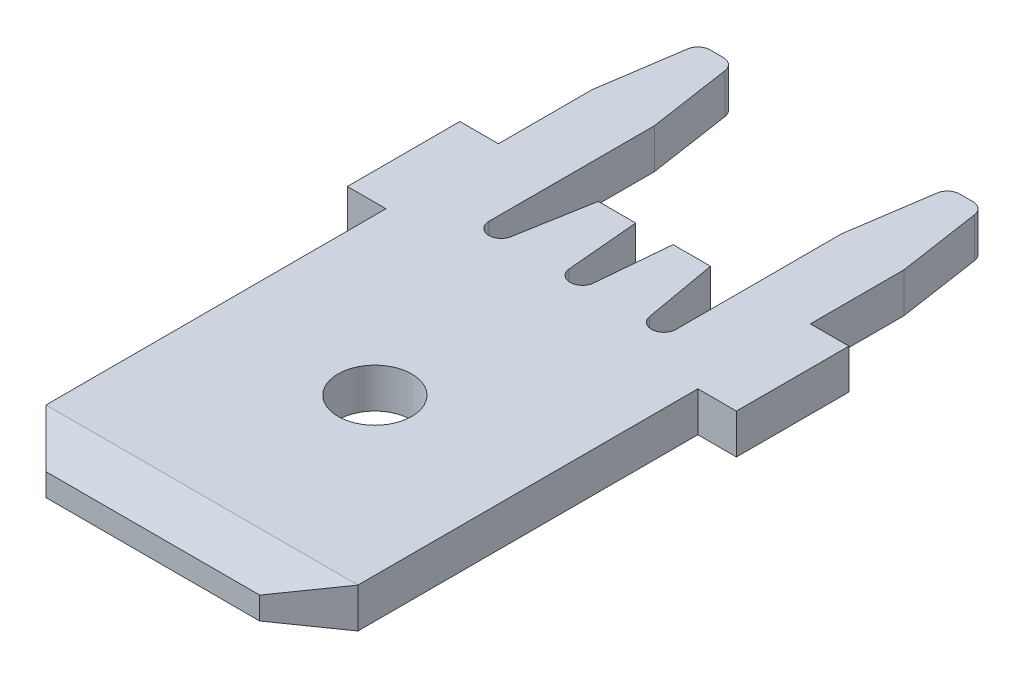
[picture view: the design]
ISO-10303-21;
HEADER;
FILE_DESCRIPTION(('STEP AP214'),'2;1');
FILE_NAME('part.step','',(''),(''),'','','');
FILE_SCHEMA(('AUTOMOTIVE_DESIGN { 1 0 10303 214 1 1 1 1 }'));
ENDSEC;
DATA;
#1=APPLICATION_CONTEXT('core data for automotive mechanical design processes');
#2=APPLICATION_PROTOCOL_DEFINITION('international standard','automotive_design',2000,#1);
#3=PRODUCT_CONTEXT('',#1,'mechanical');
#4=PRODUCT('Part','Part','',(#3));
#5=PRODUCT_RELATED_PRODUCT_CATEGORY('part','',(#4));
#6=PRODUCT_DEFINITION_FORMATION('','',#4);
#7=PRODUCT_DEFINITION_CONTEXT('part definition',#1,'design');
#8=PRODUCT_DEFINITION('design','',#6,#7);
#9=PRODUCT_DEFINITION_SHAPE('','',#8);
#10=(LENGTH_UNIT() NAMED_UNIT(*) SI_UNIT(.MILLI.,.METRE.));
#11=(NAMED_UNIT(*) PLANE_ANGLE_UNIT() SI_UNIT($,.RADIAN.));
#12=(NAMED_UNIT(*) SI_UNIT($,.STERADIAN.) SOLID_ANGLE_UNIT());
#13=UNCERTAINTY_MEASURE_WITH_UNIT(LENGTH_MEASURE(1.E-05),#10,'distance_accuracy_value','');
#14=(GEOMETRIC_REPRESENTATION_CONTEXT(3) GLOBAL_UNCERTAINTY_ASSIGNED_CONTEXT((#13)) GLOBAL_UNIT_ASSIGNED_CONTEXT((#10,
#11,#12)) REPRESENTATION_CONTEXT('',''));
#15=CARTESIAN_POINT('',(0.,0.,0.));
#16=DIRECTION('',(0.,0.,1.));
#17=DIRECTION('',(1.,0.,0.));
#18=AXIS2_PLACEMENT_3D('',#15,#16,#17);
#19=CARTESIAN_POINT('',(-2.67461930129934,-0.81,-9.24999999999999));
#20=DIRECTION('',(0.,-1.,0.));
#21=DIRECTION('',(0.,0.,-1.));
#22=AXIS2_PLACEMENT_3D('',#19,#20,#21);
#23=PLANE('',#22);
#24=DIRECTION('',(0.,0.,1.));
#25=VECTOR('',#24,1.);
#26=CARTESIAN_POINT('',(3.175,-0.81,4.52));
#27=LINE('',#26,#25);
#28=CARTESIAN_POINT('',(3.175,-0.81,-3.4));
#29=VERTEX_POINT('',#28);
#30=CARTESIAN_POINT('',(3.175,-0.81,3.51999999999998));
#31=VERTEX_POINT('',#30);
#32=EDGE_CURVE('E769',#29,#31,#27,.T.);
#33=ORIENTED_EDGE('',*,*,#32,.T.);
#34=DIRECTION('',(-1.,0.,0.));
#35=VECTOR('',#34,1.);
#36=CARTESIAN_POINT('',(-3.175,-0.81,3.51999999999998));
#37=LINE('',#36,#35);
#38=CARTESIAN_POINT('',(-3.175,-0.81,3.51999999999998));
#39=VERTEX_POINT('',#38);
#40=EDGE_CURVE('E262',#31,#39,#37,.T.);
#41=ORIENTED_EDGE('',*,*,#40,.T.);
#42=DIRECTION('',(0.,0.,-1.));
#43=VECTOR('',#42,1.);
#44=CARTESIAN_POINT('',(-3.175,-0.81,4.52));
#45=LINE('',#44,#43);
#46=CARTESIAN_POINT('',(-3.175,-0.81,-3.4));
#47=VERTEX_POINT('',#46);
#48=EDGE_CURVE('E256',#39,#47,#45,.T.);
#49=ORIENTED_EDGE('',*,*,#48,.T.);
#50=DIRECTION('',(-1.,0.,0.));
#51=VECTOR('',#50,1.);
#52=CARTESIAN_POINT('',(-3.175,-0.81,-3.4));
#53=LINE('',#52,#51);
#54=CARTESIAN_POINT('',(-3.96,-0.81,-3.4));
#55=VERTEX_POINT('',#54);
#56=EDGE_CURVE('E260',#47,#55,#53,.T.);
#57=ORIENTED_EDGE('',*,*,#56,.T.);
#58=DIRECTION('',(0.,0.,-1.));
#59=VECTOR('',#58,1.);
#60=CARTESIAN_POINT('',(-3.96,-0.81,-3.4));
#61=LINE('',#60,#59);
#62=CARTESIAN_POINT('',(-3.96,-0.81,-5.69));
#63=VERTEX_POINT('',#62);
#64=EDGE_CURVE('E276',#55,#63,#61,.T.);
#65=ORIENTED_EDGE('',*,*,#64,.T.);
#66=DIRECTION('',(1.,0.,0.));
#67=VECTOR('',#66,1.);
#68=CARTESIAN_POINT('',(-3.96,-0.81,-5.69));
#69=LINE('',#68,#67);
#70=CARTESIAN_POINT('',(-3.175,-0.81,-5.69));
#71=VERTEX_POINT('',#70);
#72=EDGE_CURVE('E705',#63,#71,#69,.T.);
#73=ORIENTED_EDGE('',*,*,#72,.T.);
#74=DIRECTION('',(0.,0.,-1.));
#75=VECTOR('',#74,1.);
#76=CARTESIAN_POINT('',(-3.175,-0.81,-5.69));
#77=LINE('',#76,#75);
#78=CARTESIAN_POINT('',(-3.175,-0.81,-7.595));
#79=VERTEX_POINT('',#78);
#80=EDGE_CURVE('E846',#71,#79,#77,.T.);
#81=ORIENTED_EDGE('',*,*,#80,.T.);
#82=DIRECTION('',(0.147959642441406,0.,-0.988993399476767));
#83=VECTOR('',#82,1.);
#84=CARTESIAN_POINT('',(-3.175,-0.81,-7.595));
#85=LINE('',#84,#83);
#86=CARTESIAN_POINT('',(-2.92186765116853,-0.81,-9.28698991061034));
#87=VERTEX_POINT('',#86);
#88=EDGE_CURVE('E848',#79,#87,#85,.T.);
#89=ORIENTED_EDGE('',*,*,#88,.T.);
#90=CARTESIAN_POINT('',(-2.67461930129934,-0.81,-9.24999999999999));
#91=DIRECTION('',(0.,-1.,0.));
#92=DIRECTION('',(0.,0.,-1.));
#93=AXIS2_PLACEMENT_3D('',#90,#91,#92);
#94=CIRCLE('',#93,0.25);
#95=CARTESIAN_POINT('',(-2.67461930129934,-0.81,-9.49999999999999));
#96=VERTEX_POINT('',#95);
#97=EDGE_CURVE('E850',#87,#96,#94,.T.);
#98=ORIENTED_EDGE('',*,*,#97,.T.);
#99=DIRECTION('',(1.,0.,0.));
#100=VECTOR('',#99,1.);
#101=CARTESIAN_POINT('',(-2.67461930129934,-0.81,-9.49999999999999));
#102=LINE('',#101,#100);
#103=CARTESIAN_POINT('',(-2.40538069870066,-0.81,-9.49999999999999));
#104=VERTEX_POINT('',#103);
#105=EDGE_CURVE('E856',#96,#104,#102,.T.);
#106=ORIENTED_EDGE('',*,*,#105,.T.);
#107=CARTESIAN_POINT('',(-2.40538069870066,-0.81,-9.24999999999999));
#108=DIRECTION('',(0.,-1.,0.));
#109=DIRECTION('',(0.,0.,-1.));
#110=AXIS2_PLACEMENT_3D('',#107,#108,#109);
#111=CIRCLE('',#110,0.25);
#112=CARTESIAN_POINT('',(-2.15813234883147,-0.81,-9.28698991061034));
#113=VERTEX_POINT('',#112);
#114=EDGE_CURVE('E858',#104,#113,#111,.T.);
#115=ORIENTED_EDGE('',*,*,#114,.T.);
#116=DIRECTION('',(0.147959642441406,0.,0.988993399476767));
#117=VECTOR('',#116,1.);
#118=CARTESIAN_POINT('',(-1.905,-0.81,-7.595));
#119=LINE('',#118,#117);
#120=CARTESIAN_POINT('',(-1.905,-0.81,-7.595));
#121=VERTEX_POINT('',#120);
#122=EDGE_CURVE('E860',#113,#121,#119,.T.);
#123=ORIENTED_EDGE('',*,*,#122,.T.);
#124=DIRECTION('',(0.,0.,1.));
#125=VECTOR('',#124,1.);
#126=CARTESIAN_POINT('',(-1.905,-0.81,-4.22599632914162));
#127=LINE('',#126,#125);
#128=CARTESIAN_POINT('',(-1.905,-0.81,-4.22599632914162));
#129=VERTEX_POINT('',#128);
#130=EDGE_CURVE('E862',#121,#129,#127,.T.);
#131=ORIENTED_EDGE('',*,*,#130,.T.);
#132=CARTESIAN_POINT('',(-1.655,-0.81,-4.22599632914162));
#133=DIRECTION('',(0.,1.,0.));
#134=DIRECTION('',(0.,0.,1.));
#135=AXIS2_PLACEMENT_3D('',#132,#133,#134);
#136=CIRCLE('',#135,0.25);
#137=CARTESIAN_POINT('',(-1.40879806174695,-0.81,-4.18258428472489));
#138=VERTEX_POINT('',#137);
#139=EDGE_CURVE('E864',#129,#138,#136,.T.);
#140=ORIENTED_EDGE('',*,*,#139,.T.);
#141=DIRECTION('',(0.173648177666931,0.,-0.984807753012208));
#142=VECTOR('',#141,1.);
#143=CARTESIAN_POINT('',(-1.143,-0.81,-5.69));
#144=LINE('',#143,#142);
#145=CARTESIAN_POINT('',(-1.143,-0.81,-5.69));
#146=VERTEX_POINT('',#145);
#147=EDGE_CURVE('E866',#138,#146,#144,.T.);
#148=ORIENTED_EDGE('',*,*,#147,.T.);
#149=DIRECTION('',(1.,0.,0.));
#150=VECTOR('',#149,1.);
#151=CARTESIAN_POINT('',(-0.381000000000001,-0.81,-5.69));
#152=LINE('',#151,#150);
#153=CARTESIAN_POINT('',(-0.381000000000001,-0.81,-5.69));
#154=VERTEX_POINT('',#153);
#155=EDGE_CURVE('E868',#146,#154,#152,.T.);
#156=ORIENTED_EDGE('',*,*,#155,.T.);
#157=DIRECTION('',(0.0884604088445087,0.,0.996079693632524));
#158=VECTOR('',#157,1.);
#159=CARTESIAN_POINT('',(-0.381000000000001,-0.81,-5.69));
#160=LINE('',#159,#158);
#161=CARTESIAN_POINT('',(-0.24901992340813,-0.81,-4.2038812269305));
#162=VERTEX_POINT('',#161);
#163=EDGE_CURVE('E870',#154,#162,#160,.T.);
#164=ORIENTED_EDGE('',*,*,#163,.T.);
#165=CARTESIAN_POINT('',(0.,-0.81,-4.22599632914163));
#166=DIRECTION('',(0.,1.,0.));
#167=DIRECTION('',(0.,0.,-1.));
#168=AXIS2_PLACEMENT_3D('',#165,#166,#167);
#169=CIRCLE('',#168,0.25);
#170=CARTESIAN_POINT('',(0.249019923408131,-0.81,-4.2038812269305));
#171=VERTEX_POINT('',#170);
#172=EDGE_CURVE('E872',#162,#171,#169,.T.);
#173=ORIENTED_EDGE('',*,*,#172,.T.);
#174=DIRECTION('',(0.0884604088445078,0.,-0.996079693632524));
#175=VECTOR('',#174,1.);
#176=CARTESIAN_POINT('',(0.381000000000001,-0.81,-5.69));
#177=LINE('',#176,#175);
#178=CARTESIAN_POINT('',(0.381000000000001,-0.81,-5.69));
#179=VERTEX_POINT('',#178);
#180=EDGE_CURVE('E874',#171,#179,#177,.T.);
#181=ORIENTED_EDGE('',*,*,#180,.T.);
#182=DIRECTION('',(1.,0.,0.));
#183=VECTOR('',#182,1.);
#184=CARTESIAN_POINT('',(0.381000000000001,-0.81,-5.69));
#185=LINE('',#184,#183);
#186=CARTESIAN_POINT('',(1.143,-0.81,-5.69));
#187=VERTEX_POINT('',#186);
#188=EDGE_CURVE('E876',#179,#187,#185,.T.);
#189=ORIENTED_EDGE('',*,*,#188,.T.);
#190=DIRECTION('',(0.173648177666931,0.,0.984807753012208));
#191=VECTOR('',#190,1.);
#192=CARTESIAN_POINT('',(1.143,-0.81,-5.69));
#193=LINE('',#192,#191);
#194=CARTESIAN_POINT('',(1.40879806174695,-0.81,-4.18258428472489));
#195=VERTEX_POINT('',#194);
#196=EDGE_CURVE('E878',#187,#195,#193,.T.);
#197=ORIENTED_EDGE('',*,*,#196,.T.);
#198=CARTESIAN_POINT('',(1.655,-0.81,-4.22599632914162));
#199=DIRECTION('',(0.,1.,0.));
#200=DIRECTION('',(0.,0.,-1.));
#201=AXIS2_PLACEMENT_3D('',#198,#199,#200);
#202=CIRCLE('',#201,0.25);
#203=CARTESIAN_POINT('',(1.905,-0.81,-4.22599632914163));
#204=VERTEX_POINT('',#203);
#205=EDGE_CURVE('E880',#195,#204,#202,.T.);
#206=ORIENTED_EDGE('',*,*,#205,.T.);
#207=DIRECTION('',(0.,0.,-1.));
#208=VECTOR('',#207,1.);
#209=CARTESIAN_POINT('',(1.905,-0.81,-4.22599632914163));
#210=LINE('',#209,#208);
#211=CARTESIAN_POINT('',(1.905,-0.81,-7.595));
#212=VERTEX_POINT('',#211);
#213=EDGE_CURVE('E882',#204,#212,#210,.T.);
#214=ORIENTED_EDGE('',*,*,#213,.T.);
#215=DIRECTION('',(0.147959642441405,0.,-0.988993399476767));
#216=VECTOR('',#215,1.);
#217=CARTESIAN_POINT('',(1.905,-0.81,-7.595));
#218=LINE('',#217,#216);
#219=CARTESIAN_POINT('',(2.15813234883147,-0.81,-9.28698991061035));
#220=VERTEX_POINT('',#219);
#221=EDGE_CURVE('E884',#212,#220,#218,.T.);
#222=ORIENTED_EDGE('',*,*,#221,.T.);
#223=CARTESIAN_POINT('',(2.40538069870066,-0.81,-9.25));
#224=DIRECTION('',(0.,-1.,0.));
#225=DIRECTION('',(0.,0.,1.));
#226=AXIS2_PLACEMENT_3D('',#223,#224,#225);
#227=CIRCLE('',#226,0.25);
#228=CARTESIAN_POINT('',(2.40538069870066,-0.81,-9.5));
#229=VERTEX_POINT('',#228);
#230=EDGE_CURVE('E886',#220,#229,#227,.T.);
#231=ORIENTED_EDGE('',*,*,#230,.T.);
#232=DIRECTION('',(1.,0.,0.));
#233=VECTOR('',#232,1.);
#234=CARTESIAN_POINT('',(2.67461930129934,-0.81,-9.5));
#235=LINE('',#234,#233);
#236=CARTESIAN_POINT('',(2.67461930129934,-0.81,-9.5));
#237=VERTEX_POINT('',#236);
#238=EDGE_CURVE('E888',#229,#237,#235,.T.);
#239=ORIENTED_EDGE('',*,*,#238,.T.);
#240=CARTESIAN_POINT('',(2.67461930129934,-0.81,-9.25));
#241=DIRECTION('',(0.,-1.,0.));
#242=DIRECTION('',(0.,0.,1.));
#243=AXIS2_PLACEMENT_3D('',#240,#241,#242);
#244=CIRCLE('',#243,0.25);
#245=CARTESIAN_POINT('',(2.92186765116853,-0.81,-9.28698991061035));
#246=VERTEX_POINT('',#245);
#247=EDGE_CURVE('E890',#237,#246,#244,.T.);
#248=ORIENTED_EDGE('',*,*,#247,.T.);
#249=DIRECTION('',(0.147959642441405,0.,0.988993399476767));
#250=VECTOR('',#249,1.);
#251=CARTESIAN_POINT('',(3.175,-0.81,-7.595));
#252=LINE('',#251,#250);
#253=CARTESIAN_POINT('',(3.175,-0.81,-7.595));
#254=VERTEX_POINT('',#253);
#255=EDGE_CURVE('E892',#246,#254,#252,.T.);
#256=ORIENTED_EDGE('',*,*,#255,.T.);
#257=DIRECTION('',(0.,0.,1.));
#258=VECTOR('',#257,1.);
#259=CARTESIAN_POINT('',(3.175,-0.81,-5.69));
#260=LINE('',#259,#258);
#261=CARTESIAN_POINT('',(3.175,-0.81,-5.69));
#262=VERTEX_POINT('',#261);
#263=EDGE_CURVE('E894',#254,#262,#260,.T.);
#264=ORIENTED_EDGE('',*,*,#263,.T.);
#265=DIRECTION('',(1.,0.,0.));
#266=VECTOR('',#265,1.);
#267=CARTESIAN_POINT('',(3.96,-0.81,-5.69));
#268=LINE('',#267,#266);
#269=CARTESIAN_POINT('',(3.96,-0.81,-5.69));
#270=VERTEX_POINT('',#269);
#271=EDGE_CURVE('E896',#262,#270,#268,.T.);
#272=ORIENTED_EDGE('',*,*,#271,.T.);
#273=DIRECTION('',(0.,0.,1.));
#274=VECTOR('',#273,1.);
#275=CARTESIAN_POINT('',(3.96,-0.81,-3.4));
#276=LINE('',#275,#274);
#277=CARTESIAN_POINT('',(3.96,-0.81,-3.4));
#278=VERTEX_POINT('',#277);
#279=EDGE_CURVE('E898',#270,#278,#276,.T.);
#280=ORIENTED_EDGE('',*,*,#279,.T.);
#281=DIRECTION('',(-1.,0.,0.));
#282=VECTOR('',#281,1.);
#283=CARTESIAN_POINT('',(3.175,-0.81,-3.4));
#284=LINE('',#283,#282);
#285=EDGE_CURVE('E900',#278,#29,#284,.T.);
#286=ORIENTED_EDGE('',*,*,#285,.T.);
#287=EDGE_LOOP('',(#33,#41,#49,#57,#65,#73,#81,#89,#98,#106,#115,#123,#131,#140,#148,#156,#164,
#173,#181,#189,#197,#206,#214,#222,#231,#239,#248,#256,#264,#272,#280,#286));
#288=FACE_BOUND('',#287,.T.);
#289=CARTESIAN_POINT('',(0.,-0.81,0.));
#290=DIRECTION('',(0.,-1.,0.));
#291=DIRECTION('',(0.,0.,-1.));
#292=AXIS2_PLACEMENT_3D('',#289,#290,#291);
#293=CIRCLE('',#292,0.75);
#294=CARTESIAN_POINT('',(0.,-0.81,-0.75));
#295=VERTEX_POINT('',#294);
#296=EDGE_CURVE('E317',#295,#295,#293,.T.);
#297=ORIENTED_EDGE('',*,*,#296,.F.);
#298=EDGE_LOOP('',(#297));
#299=FACE_BOUND('',#298,.T.);
#300=ADVANCED_FACE('F34',(#288,#299),#23,.T.);
#301=CARTESIAN_POINT('',(-2.67461930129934,0.,-9.24999999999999));
#302=DIRECTION('',(0.,-1.,0.));
#303=DIRECTION('',(0.,0.,-1.));
#304=AXIS2_PLACEMENT_3D('',#301,#302,#303);
#305=PLANE('',#304);
#306=DIRECTION('',(0.,0.,-1.));
#307=VECTOR('',#306,1.);
#308=CARTESIAN_POINT('',(-3.175,0.,4.52));
#309=LINE('',#308,#307);
#310=CARTESIAN_POINT('',(-3.175,0.,3.51999999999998));
#311=VERTEX_POINT('',#310);
#312=CARTESIAN_POINT('',(-3.175,0.,-3.4));
#313=VERTEX_POINT('',#312);
#314=EDGE_CURVE('E280',#311,#313,#309,.T.);
#315=ORIENTED_EDGE('',*,*,#314,.F.);
#316=DIRECTION('',(1.,0.,0.));
#317=VECTOR('',#316,1.);
#318=CARTESIAN_POINT('',(-2.67461930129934,0.,3.51999999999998));
#319=LINE('',#318,#317);
#320=CARTESIAN_POINT('',(3.175,0.,3.51999999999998));
#321=VERTEX_POINT('',#320);
#322=EDGE_CURVE('E292',#311,#321,#319,.T.);
#323=ORIENTED_EDGE('',*,*,#322,.T.);
#324=DIRECTION('',(0.,0.,1.));
#325=VECTOR('',#324,1.);
#326=CARTESIAN_POINT('',(3.175,0.,4.52));
#327=LINE('',#326,#325);
#328=CARTESIAN_POINT('',(3.175,0.,-3.4));
#329=VERTEX_POINT('',#328);
#330=EDGE_CURVE('E267',#329,#321,#327,.T.);
#331=ORIENTED_EDGE('',*,*,#330,.F.);
#332=DIRECTION('',(-1.,0.,0.));
#333=VECTOR('',#332,1.);
#334=CARTESIAN_POINT('',(3.175,0.,-3.4));
#335=LINE('',#334,#333);
#336=CARTESIAN_POINT('',(3.96,0.,-3.4));
#337=VERTEX_POINT('',#336);
#338=EDGE_CURVE('E762',#337,#329,#335,.T.);
#339=ORIENTED_EDGE('',*,*,#338,.F.);
#340=DIRECTION('',(0.,0.,1.));
#341=VECTOR('',#340,1.);
#342=CARTESIAN_POINT('',(3.96,0.,-3.4));
#343=LINE('',#342,#341);
#344=CARTESIAN_POINT('',(3.96,0.,-5.69));
#345=VERTEX_POINT('',#344);
#346=EDGE_CURVE('E760',#345,#337,#343,.T.);
#347=ORIENTED_EDGE('',*,*,#346,.F.);
#348=DIRECTION('',(1.,0.,0.));
#349=VECTOR('',#348,1.);
#350=CARTESIAN_POINT('',(3.96,0.,-5.69));
#351=LINE('',#350,#349);
#352=CARTESIAN_POINT('',(3.175,0.,-5.69));
#353=VERTEX_POINT('',#352);
#354=EDGE_CURVE('E758',#353,#345,#351,.T.);
#355=ORIENTED_EDGE('',*,*,#354,.F.);
#356=DIRECTION('',(0.,0.,1.));
#357=VECTOR('',#356,1.);
#358=CARTESIAN_POINT('',(3.175,0.,-5.69));
#359=LINE('',#358,#357);
#360=CARTESIAN_POINT('',(3.175,0.,-7.595));
#361=VERTEX_POINT('',#360);
#362=EDGE_CURVE('E756',#361,#353,#359,.T.);
#363=ORIENTED_EDGE('',*,*,#362,.F.);
#364=DIRECTION('',(0.147959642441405,0.,0.988993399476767));
#365=VECTOR('',#364,1.);
#366=CARTESIAN_POINT('',(3.175,0.,-7.595));
#367=LINE('',#366,#365);
#368=CARTESIAN_POINT('',(2.92186765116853,0.,-9.28698991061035));
#369=VERTEX_POINT('',#368);
#370=EDGE_CURVE('E754',#369,#361,#367,.T.);
#371=ORIENTED_EDGE('',*,*,#370,.F.);
#372=CARTESIAN_POINT('',(2.67461930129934,0.,-9.25));
#373=DIRECTION('',(0.,-1.,0.));
#374=DIRECTION('',(0.,0.,1.));
#375=AXIS2_PLACEMENT_3D('',#372,#373,#374);
#376=CIRCLE('',#375,0.25);
#377=CARTESIAN_POINT('',(2.67461930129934,0.,-9.5));
#378=VERTEX_POINT('',#377);
#379=EDGE_CURVE('E752',#378,#369,#376,.T.);
#380=ORIENTED_EDGE('',*,*,#379,.F.);
#381=DIRECTION('',(1.,0.,0.));
#382=VECTOR('',#381,1.);
#383=CARTESIAN_POINT('',(2.67461930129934,0.,-9.5));
#384=LINE('',#383,#382);
#385=CARTESIAN_POINT('',(2.40538069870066,0.,-9.5));
#386=VERTEX_POINT('',#385);
#387=EDGE_CURVE('E750',#386,#378,#384,.T.);
#388=ORIENTED_EDGE('',*,*,#387,.F.);
#389=CARTESIAN_POINT('',(2.40538069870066,0.,-9.25));
#390=DIRECTION('',(0.,-1.,0.));
#391=DIRECTION('',(0.,0.,1.));
#392=AXIS2_PLACEMENT_3D('',#389,#390,#391);
#393=CIRCLE('',#392,0.25);
#394=CARTESIAN_POINT('',(2.15813234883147,0.,-9.28698991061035));
#395=VERTEX_POINT('',#394);
#396=EDGE_CURVE('E748',#395,#386,#393,.T.);
#397=ORIENTED_EDGE('',*,*,#396,.F.);
#398=DIRECTION('',(0.147959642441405,0.,-0.988993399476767));
#399=VECTOR('',#398,1.);
#400=CARTESIAN_POINT('',(1.905,0.,-7.595));
#401=LINE('',#400,#399);
#402=CARTESIAN_POINT('',(1.905,0.,-7.595));
#403=VERTEX_POINT('',#402);
#404=EDGE_CURVE('E746',#403,#395,#401,.T.);
#405=ORIENTED_EDGE('',*,*,#404,.F.);
#406=DIRECTION('',(0.,0.,-1.));
#407=VECTOR('',#406,1.);
#408=CARTESIAN_POINT('',(1.905,0.,-4.22599632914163));
#409=LINE('',#408,#407);
#410=CARTESIAN_POINT('',(1.905,0.,-4.22599632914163));
#411=VERTEX_POINT('',#410);
#412=EDGE_CURVE('E744',#411,#403,#409,.T.);
#413=ORIENTED_EDGE('',*,*,#412,.F.);
#414=CARTESIAN_POINT('',(1.655,0.,-4.22599632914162));
#415=DIRECTION('',(0.,1.,0.));
#416=DIRECTION('',(0.,0.,-1.));
#417=AXIS2_PLACEMENT_3D('',#414,#415,#416);
#418=CIRCLE('',#417,0.25);
#419=CARTESIAN_POINT('',(1.40879806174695,0.,-4.18258428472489));
#420=VERTEX_POINT('',#419);
#421=EDGE_CURVE('E742',#420,#411,#418,.T.);
#422=ORIENTED_EDGE('',*,*,#421,.F.);
#423=DIRECTION('',(0.173648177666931,0.,0.984807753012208));
#424=VECTOR('',#423,1.);
#425=CARTESIAN_POINT('',(1.143,0.,-5.69));
#426=LINE('',#425,#424);
#427=CARTESIAN_POINT('',(1.143,0.,-5.69));
#428=VERTEX_POINT('',#427);
#429=EDGE_CURVE('E740',#428,#420,#426,.T.);
#430=ORIENTED_EDGE('',*,*,#429,.F.);
#431=DIRECTION('',(1.,0.,0.));
#432=VECTOR('',#431,1.);
#433=CARTESIAN_POINT('',(0.381000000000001,0.,-5.69));
#434=LINE('',#433,#432);
#435=CARTESIAN_POINT('',(0.381000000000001,0.,-5.69));
#436=VERTEX_POINT('',#435);
#437=EDGE_CURVE('E738',#436,#428,#434,.T.);
#438=ORIENTED_EDGE('',*,*,#437,.F.);
#439=DIRECTION('',(0.0884604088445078,0.,-0.996079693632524));
#440=VECTOR('',#439,1.);
#441=CARTESIAN_POINT('',(0.381000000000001,0.,-5.69));
#442=LINE('',#441,#440);
#443=CARTESIAN_POINT('',(0.249019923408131,0.,-4.2038812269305));
#444=VERTEX_POINT('',#443);
#445=EDGE_CURVE('E736',#444,#436,#442,.T.);
#446=ORIENTED_EDGE('',*,*,#445,.F.);
#447=CARTESIAN_POINT('',(0.,0.,-4.22599632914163));
#448=DIRECTION('',(0.,1.,0.));
#449=DIRECTION('',(0.,0.,-1.));
#450=AXIS2_PLACEMENT_3D('',#447,#448,#449);
#451=CIRCLE('',#450,0.25);
#452=CARTESIAN_POINT('',(-0.24901992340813,0.,-4.2038812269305));
#453=VERTEX_POINT('',#452);
#454=EDGE_CURVE('E734',#453,#444,#451,.T.);
#455=ORIENTED_EDGE('',*,*,#454,.F.);
#456=DIRECTION('',(0.0884604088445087,0.,0.996079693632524));
#457=VECTOR('',#456,1.);
#458=CARTESIAN_POINT('',(-0.381000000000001,0.,-5.69));
#459=LINE('',#458,#457);
#460=CARTESIAN_POINT('',(-0.381000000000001,0.,-5.69));
#461=VERTEX_POINT('',#460);
#462=EDGE_CURVE('E732',#461,#453,#459,.T.);
#463=ORIENTED_EDGE('',*,*,#462,.F.);
#464=DIRECTION('',(1.,0.,0.));
#465=VECTOR('',#464,1.);
#466=CARTESIAN_POINT('',(-0.381000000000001,0.,-5.69));
#467=LINE('',#466,#465);
#468=CARTESIAN_POINT('',(-1.143,0.,-5.69));
#469=VERTEX_POINT('',#468);
#470=EDGE_CURVE('E730',#469,#461,#467,.T.);
#471=ORIENTED_EDGE('',*,*,#470,.F.);
#472=DIRECTION('',(0.173648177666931,0.,-0.984807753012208));
#473=VECTOR('',#472,1.);
#474=CARTESIAN_POINT('',(-1.143,0.,-5.69));
#475=LINE('',#474,#473);
#476=CARTESIAN_POINT('',(-1.40879806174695,0.,-4.18258428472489));
#477=VERTEX_POINT('',#476);
#478=EDGE_CURVE('E728',#477,#469,#475,.T.);
#479=ORIENTED_EDGE('',*,*,#478,.F.);
#480=CARTESIAN_POINT('',(-1.655,0.,-4.22599632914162));
#481=DIRECTION('',(0.,1.,0.));
#482=DIRECTION('',(0.,0.,1.));
#483=AXIS2_PLACEMENT_3D('',#480,#481,#482);
#484=CIRCLE('',#483,0.25);
#485=CARTESIAN_POINT('',(-1.905,0.,-4.22599632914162));
#486=VERTEX_POINT('',#485);
#487=EDGE_CURVE('E726',#486,#477,#484,.T.);
#488=ORIENTED_EDGE('',*,*,#487,.F.);
#489=DIRECTION('',(0.,0.,1.));
#490=VECTOR('',#489,1.);
#491=CARTESIAN_POINT('',(-1.905,0.,-4.22599632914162));
#492=LINE('',#491,#490);
#493=CARTESIAN_POINT('',(-1.905,0.,-7.595));
#494=VERTEX_POINT('',#493);
#495=EDGE_CURVE('E724',#494,#486,#492,.T.);
#496=ORIENTED_EDGE('',*,*,#495,.F.);
#497=DIRECTION('',(0.147959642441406,0.,0.988993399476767));
#498=VECTOR('',#497,1.);
#499=CARTESIAN_POINT('',(-1.905,0.,-7.595));
#500=LINE('',#499,#498);
#501=CARTESIAN_POINT('',(-2.15813234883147,0.,-9.28698991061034));
#502=VERTEX_POINT('',#501);
#503=EDGE_CURVE('E722',#502,#494,#500,.T.);
#504=ORIENTED_EDGE('',*,*,#503,.F.);
#505=CARTESIAN_POINT('',(-2.40538069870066,0.,-9.24999999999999));
#506=DIRECTION('',(0.,-1.,0.));
#507=DIRECTION('',(0.,0.,-1.));
#508=AXIS2_PLACEMENT_3D('',#505,#506,#507);
#509=CIRCLE('',#508,0.25);
#510=CARTESIAN_POINT('',(-2.40538069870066,0.,-9.49999999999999));
#511=VERTEX_POINT('',#510);
#512=EDGE_CURVE('E720',#511,#502,#509,.T.);
#513=ORIENTED_EDGE('',*,*,#512,.F.);
#514=DIRECTION('',(1.,0.,0.));
#515=VECTOR('',#514,1.);
#516=CARTESIAN_POINT('',(-2.67461930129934,0.,-9.49999999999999));
#517=LINE('',#516,#515);
#518=CARTESIAN_POINT('',(-2.67461930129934,0.,-9.49999999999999));
#519=VERTEX_POINT('',#518);
#520=EDGE_CURVE('E718',#519,#511,#517,.T.);
#521=ORIENTED_EDGE('',*,*,#520,.F.);
#522=CARTESIAN_POINT('',(-2.67461930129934,0.,-9.24999999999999));
#523=DIRECTION('',(0.,-1.,0.));
#524=DIRECTION('',(0.,0.,-1.));
#525=AXIS2_PLACEMENT_3D('',#522,#523,#524);
#526=CIRCLE('',#525,0.25);
#527=CARTESIAN_POINT('',(-2.92186765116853,0.,-9.28698991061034));
#528=VERTEX_POINT('',#527);
#529=EDGE_CURVE('E716',#528,#519,#526,.T.);
#530=ORIENTED_EDGE('',*,*,#529,.F.);
#531=DIRECTION('',(0.147959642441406,0.,-0.988993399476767));
#532=VECTOR('',#531,1.);
#533=CARTESIAN_POINT('',(-3.175,0.,-7.595));
#534=LINE('',#533,#532);
#535=CARTESIAN_POINT('',(-3.175,0.,-7.595));
#536=VERTEX_POINT('',#535);
#537=EDGE_CURVE('E711',#536,#528,#534,.T.);
#538=ORIENTED_EDGE('',*,*,#537,.F.);
#539=DIRECTION('',(0.,0.,-1.));
#540=VECTOR('',#539,1.);
#541=CARTESIAN_POINT('',(-3.175,0.,-5.69));
#542=LINE('',#541,#540);
#543=CARTESIAN_POINT('',(-3.175,0.,-5.69));
#544=VERTEX_POINT('',#543);
#545=EDGE_CURVE('E709',#544,#536,#542,.T.);
#546=ORIENTED_EDGE('',*,*,#545,.F.);
#547=DIRECTION('',(1.,0.,0.));
#548=VECTOR('',#547,1.);
#549=CARTESIAN_POINT('',(-3.96,0.,-5.69));
#550=LINE('',#549,#548);
#551=CARTESIAN_POINT('',(-3.96,0.,-5.69));
#552=VERTEX_POINT('',#551);
#553=EDGE_CURVE('E701',#552,#544,#550,.T.);
#554=ORIENTED_EDGE('',*,*,#553,.F.);
#555=DIRECTION('',(0.,0.,-1.));
#556=VECTOR('',#555,1.);
#557=CARTESIAN_POINT('',(-3.96,0.,-3.4));
#558=LINE('',#557,#556);
#559=CARTESIAN_POINT('',(-3.96,0.,-3.4));
#560=VERTEX_POINT('',#559);
#561=EDGE_CURVE('E697',#560,#552,#558,.T.);
#562=ORIENTED_EDGE('',*,*,#561,.F.);
#563=DIRECTION('',(-1.,0.,0.));
#564=VECTOR('',#563,1.);
#565=CARTESIAN_POINT('',(-3.175,0.,-3.4));
#566=LINE('',#565,#564);
#567=EDGE_CURVE('E316',#313,#560,#566,.T.);
#568=ORIENTED_EDGE('',*,*,#567,.F.);
#569=EDGE_LOOP('',(#315,#323,#331,#339,#347,#355,#363,#371,#380,#388,#397,#405,#413,#422,#430,
#438,#446,#455,#463,#471,#479,#488,#496,#504,#513,#521,#530,#538,#546,#554,#562,#568));
#570=FACE_BOUND('',#569,.T.);
#571=CARTESIAN_POINT('',(0.,0.,0.));
#572=DIRECTION('',(0.,-1.,0.));
#573=DIRECTION('',(0.,0.,-1.));
#574=AXIS2_PLACEMENT_3D('',#571,#572,#573);
#575=CIRCLE('',#574,0.75);
#576=CARTESIAN_POINT('',(0.,0.,-0.75));
#577=VERTEX_POINT('',#576);
#578=EDGE_CURVE('E977',#577,#577,#575,.T.);
#579=ORIENTED_EDGE('',*,*,#578,.T.);
#580=EDGE_LOOP('',(#579));
#581=FACE_BOUND('',#580,.T.);
#582=ADVANCED_FACE('F311',(#570,#581),#305,.F.);
#583=CARTESIAN_POINT('',(-3.175,-0.81,4.52));
#584=DIRECTION('',(1.,0.,0.));
#585=DIRECTION('',(0.,0.,-1.));
#586=AXIS2_PLACEMENT_3D('',#583,#584,#585);
#587=PLANE('',#586);
#588=ORIENTED_EDGE('',*,*,#48,.F.);
#589=DIRECTION('',(0.,1.,0.));
#590=VECTOR('',#589,1.);
#591=CARTESIAN_POINT('',(-3.175,-0.81,3.52));
#592=LINE('',#591,#590);
#593=EDGE_CURVE('E295',#39,#311,#592,.T.);
#594=ORIENTED_EDGE('',*,*,#593,.T.);
#595=ORIENTED_EDGE('',*,*,#314,.T.);
#596=DIRECTION('',(0.,1.,0.));
#597=VECTOR('',#596,1.);
#598=CARTESIAN_POINT('',(-3.175,-0.81,-3.4));
#599=LINE('',#598,#597);
#600=EDGE_CURVE('E272',#47,#313,#599,.T.);
#601=ORIENTED_EDGE('',*,*,#600,.F.);
#602=EDGE_LOOP('',(#588,#594,#595,#601));
#603=FACE_BOUND('',#602,.T.);
#604=ADVANCED_FACE('F278',(#603),#587,.F.);
#605=CARTESIAN_POINT('',(-3.175,-0.81,-3.4));
#606=DIRECTION('',(0.,0.,-1.));
#607=DIRECTION('',(-1.,0.,0.));
#608=AXIS2_PLACEMENT_3D('',#605,#606,#607);
#609=PLANE('',#608);
#610=ORIENTED_EDGE('',*,*,#567,.T.);
#611=DIRECTION('',(0.,1.,0.));
#612=VECTOR('',#611,1.);
#613=CARTESIAN_POINT('',(-3.96,-0.81,-3.4));
#614=LINE('',#613,#612);
#615=EDGE_CURVE('E274',#55,#560,#614,.T.);
#616=ORIENTED_EDGE('',*,*,#615,.F.);
#617=ORIENTED_EDGE('',*,*,#56,.F.);
#618=ORIENTED_EDGE('',*,*,#600,.T.);
#619=EDGE_LOOP('',(#610,#616,#617,#618));
#620=FACE_BOUND('',#619,.T.);
#621=ADVANCED_FACE('F271',(#620),#609,.F.);
#622=CARTESIAN_POINT('',(-3.96,-0.81,-3.4));
#623=DIRECTION('',(1.,0.,0.));
#624=DIRECTION('',(0.,0.,-1.));
#625=AXIS2_PLACEMENT_3D('',#622,#623,#624);
#626=PLANE('',#625);
#627=ORIENTED_EDGE('',*,*,#561,.T.);
#628=DIRECTION('',(0.,1.,0.));
#629=VECTOR('',#628,1.);
#630=CARTESIAN_POINT('',(-3.96,-0.81,-5.69));
#631=LINE('',#630,#629);
#632=EDGE_CURVE('E285',#63,#552,#631,.T.);
#633=ORIENTED_EDGE('',*,*,#632,.F.);
#634=ORIENTED_EDGE('',*,*,#64,.F.);
#635=ORIENTED_EDGE('',*,*,#615,.T.);
#636=EDGE_LOOP('',(#627,#633,#634,#635));
#637=FACE_BOUND('',#636,.T.);
#638=ADVANCED_FACE('F352',(#637),#626,.F.);
#639=CARTESIAN_POINT('',(-3.96,-0.81,-5.69));
#640=DIRECTION('',(0.,0.,1.));
#641=DIRECTION('',(1.,0.,0.));
#642=AXIS2_PLACEMENT_3D('',#639,#640,#641);
#643=PLANE('',#642);
#644=ORIENTED_EDGE('',*,*,#553,.T.);
#645=DIRECTION('',(0.,1.,0.));
#646=VECTOR('',#645,1.);
#647=CARTESIAN_POINT('',(-3.175,-0.81,-5.69));
#648=LINE('',#647,#646);
#649=EDGE_CURVE('E706',#71,#544,#648,.T.);
#650=ORIENTED_EDGE('',*,*,#649,.F.);
#651=ORIENTED_EDGE('',*,*,#72,.F.);
#652=ORIENTED_EDGE('',*,*,#632,.T.);
#653=EDGE_LOOP('',(#644,#650,#651,#652));
#654=FACE_BOUND('',#653,.T.);
#655=ADVANCED_FACE('F669',(#654),#643,.F.);
#656=CARTESIAN_POINT('',(-3.175,-0.81,-5.69));
#657=DIRECTION('',(1.,0.,0.));
#658=DIRECTION('',(0.,0.,-1.));
#659=AXIS2_PLACEMENT_3D('',#656,#657,#658);
#660=PLANE('',#659);
#661=ORIENTED_EDGE('',*,*,#545,.T.);
#662=DIRECTION('',(0.,1.,0.));
#663=VECTOR('',#662,1.);
#664=CARTESIAN_POINT('',(-3.175,-0.81,-7.595));
#665=LINE('',#664,#663);
#666=EDGE_CURVE('E841',#79,#536,#665,.T.);
#667=ORIENTED_EDGE('',*,*,#666,.F.);
#668=ORIENTED_EDGE('',*,*,#80,.F.);
#669=ORIENTED_EDGE('',*,*,#649,.T.);
#670=EDGE_LOOP('',(#661,#667,#668,#669));
#671=FACE_BOUND('',#670,.T.);
#672=ADVANCED_FACE('F659',(#671),#660,.F.);
#673=CARTESIAN_POINT('',(-3.175,-0.81,-7.595));
#674=DIRECTION('',(0.988993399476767,0.,0.147959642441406));
#675=DIRECTION('',(0.147959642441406,0.,-0.988993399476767));
#676=AXIS2_PLACEMENT_3D('',#673,#674,#675);
#677=PLANE('',#676);
#678=ORIENTED_EDGE('',*,*,#537,.T.);
#679=DIRECTION('',(0.,1.,0.));
#680=VECTOR('',#679,1.);
#681=CARTESIAN_POINT('',(-2.92186765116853,-0.81,-9.28698991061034));
#682=LINE('',#681,#680);
#683=EDGE_CURVE('E838',#87,#528,#682,.T.);
#684=ORIENTED_EDGE('',*,*,#683,.F.);
#685=ORIENTED_EDGE('',*,*,#88,.F.);
#686=ORIENTED_EDGE('',*,*,#666,.T.);
#687=EDGE_LOOP('',(#678,#684,#685,#686));
#688=FACE_BOUND('',#687,.T.);
#689=ADVANCED_FACE('F649',(#688),#677,.F.);
#690=CARTESIAN_POINT('',(-2.67461930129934,-0.81,-9.24999999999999));
#691=DIRECTION('',(0.,1.,0.));
#692=DIRECTION('',(0.,0.,1.));
#693=AXIS2_PLACEMENT_3D('',#690,#691,#692);
#694=CYLINDRICAL_SURFACE('',#693,0.25);
#695=ORIENTED_EDGE('',*,*,#529,.T.);
#696=DIRECTION('',(0.,1.,0.));
#697=VECTOR('',#696,1.);
#698=CARTESIAN_POINT('',(-2.67461930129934,-0.81,-9.49999999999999));
#699=LINE('',#698,#697);
#700=EDGE_CURVE('E835',#96,#519,#699,.T.);
#701=ORIENTED_EDGE('',*,*,#700,.F.);
#702=ORIENTED_EDGE('',*,*,#97,.F.);
#703=ORIENTED_EDGE('',*,*,#683,.T.);
#704=EDGE_LOOP('',(#695,#701,#702,#703));
#705=FACE_BOUND('',#704,.T.);
#706=ADVANCED_FACE('F639',(#705),#694,.T.);
#707=CARTESIAN_POINT('',(-2.67461930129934,-0.81,-9.49999999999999));
#708=DIRECTION('',(0.,0.,1.));
#709=DIRECTION('',(1.,0.,0.));
#710=AXIS2_PLACEMENT_3D('',#707,#708,#709);
#711=PLANE('',#710);
#712=ORIENTED_EDGE('',*,*,#520,.T.);
#713=DIRECTION('',(0.,1.,0.));
#714=VECTOR('',#713,1.);
#715=CARTESIAN_POINT('',(-2.40538069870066,-0.81,-9.49999999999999));
#716=LINE('',#715,#714);
#717=EDGE_CURVE('E832',#104,#511,#716,.T.);
#718=ORIENTED_EDGE('',*,*,#717,.F.);
#719=ORIENTED_EDGE('',*,*,#105,.F.);
#720=ORIENTED_EDGE('',*,*,#700,.T.);
#721=EDGE_LOOP('',(#712,#718,#719,#720));
#722=FACE_BOUND('',#721,.T.);
#723=ADVANCED_FACE('F629',(#722),#711,.F.);
#724=CARTESIAN_POINT('',(-2.40538069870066,-0.81,-9.24999999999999));
#725=DIRECTION('',(0.,1.,0.));
#726=DIRECTION('',(0.,0.,1.));
#727=AXIS2_PLACEMENT_3D('',#724,#725,#726);
#728=CYLINDRICAL_SURFACE('',#727,0.25);
#729=ORIENTED_EDGE('',*,*,#512,.T.);
#730=DIRECTION('',(0.,1.,0.));
#731=VECTOR('',#730,1.);
#732=CARTESIAN_POINT('',(-2.15813234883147,-0.81,-9.28698991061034));
#733=LINE('',#732,#731);
#734=EDGE_CURVE('E829',#113,#502,#733,.T.);
#735=ORIENTED_EDGE('',*,*,#734,.F.);
#736=ORIENTED_EDGE('',*,*,#114,.F.);
#737=ORIENTED_EDGE('',*,*,#717,.T.);
#738=EDGE_LOOP('',(#729,#735,#736,#737));
#739=FACE_BOUND('',#738,.T.);
#740=ADVANCED_FACE('F619',(#739),#728,.T.);
#741=CARTESIAN_POINT('',(-1.905,-0.81,-7.595));
#742=DIRECTION('',(-0.988993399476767,0.,0.147959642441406));
#743=DIRECTION('',(0.147959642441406,0.,0.988993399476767));
#744=AXIS2_PLACEMENT_3D('',#741,#742,#743);
#745=PLANE('',#744);
#746=ORIENTED_EDGE('',*,*,#503,.T.);
#747=DIRECTION('',(0.,1.,0.));
#748=VECTOR('',#747,1.);
#749=CARTESIAN_POINT('',(-1.905,-0.81,-7.595));
#750=LINE('',#749,#748);
#751=EDGE_CURVE('E826',#121,#494,#750,.T.);
#752=ORIENTED_EDGE('',*,*,#751,.F.);
#753=ORIENTED_EDGE('',*,*,#122,.F.);
#754=ORIENTED_EDGE('',*,*,#734,.T.);
#755=EDGE_LOOP('',(#746,#752,#753,#754));
#756=FACE_BOUND('',#755,.T.);
#757=ADVANCED_FACE('F609',(#756),#745,.F.);
#758=CARTESIAN_POINT('',(-1.905,-0.81,-4.22599632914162));
#759=DIRECTION('',(-1.,0.,0.));
#760=DIRECTION('',(0.,0.,1.));
#761=AXIS2_PLACEMENT_3D('',#758,#759,#760);
#762=PLANE('',#761);
#763=ORIENTED_EDGE('',*,*,#495,.T.);
#764=DIRECTION('',(0.,1.,0.));
#765=VECTOR('',#764,1.);
#766=CARTESIAN_POINT('',(-1.905,-0.81,-4.22599632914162));
#767=LINE('',#766,#765);
#768=EDGE_CURVE('E823',#129,#486,#767,.T.);
#769=ORIENTED_EDGE('',*,*,#768,.F.);
#770=ORIENTED_EDGE('',*,*,#130,.F.);
#771=ORIENTED_EDGE('',*,*,#751,.T.);
#772=EDGE_LOOP('',(#763,#769,#770,#771));
#773=FACE_BOUND('',#772,.T.);
#774=ADVANCED_FACE('F599',(#773),#762,.F.);
#775=CARTESIAN_POINT('',(-1.655,-0.81,-4.22599632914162));
#776=DIRECTION('',(0.,1.,0.));
#777=DIRECTION('',(0.,0.,1.));
#778=AXIS2_PLACEMENT_3D('',#775,#776,#777);
#779=CYLINDRICAL_SURFACE('',#778,0.25);
#780=ORIENTED_EDGE('',*,*,#487,.T.);
#781=DIRECTION('',(0.,1.,0.));
#782=VECTOR('',#781,1.);
#783=CARTESIAN_POINT('',(-1.40879806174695,-0.81,-4.18258428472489));
#784=LINE('',#783,#782);
#785=EDGE_CURVE('E820',#138,#477,#784,.T.);
#786=ORIENTED_EDGE('',*,*,#785,.F.);
#787=ORIENTED_EDGE('',*,*,#139,.F.);
#788=ORIENTED_EDGE('',*,*,#768,.T.);
#789=EDGE_LOOP('',(#780,#786,#787,#788));
#790=FACE_BOUND('',#789,.T.);
#791=ADVANCED_FACE('F589',(#790),#779,.F.);
#792=CARTESIAN_POINT('',(-1.143,-0.81,-5.69));
#793=DIRECTION('',(0.984807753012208,0.,0.173648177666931));
#794=DIRECTION('',(0.173648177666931,0.,-0.984807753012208));
#795=AXIS2_PLACEMENT_3D('',#792,#793,#794);
#796=PLANE('',#795);
#797=ORIENTED_EDGE('',*,*,#478,.T.);
#798=DIRECTION('',(0.,1.,0.));
#799=VECTOR('',#798,1.);
#800=CARTESIAN_POINT('',(-1.143,-0.81,-5.69));
#801=LINE('',#800,#799);
#802=EDGE_CURVE('E817',#146,#469,#801,.T.);
#803=ORIENTED_EDGE('',*,*,#802,.F.);
#804=ORIENTED_EDGE('',*,*,#147,.F.);
#805=ORIENTED_EDGE('',*,*,#785,.T.);
#806=EDGE_LOOP('',(#797,#803,#804,#805));
#807=FACE_BOUND('',#806,.T.);
#808=ADVANCED_FACE('F579',(#807),#796,.F.);
#809=CARTESIAN_POINT('',(-0.381000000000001,-0.81,-5.69));
#810=DIRECTION('',(0.,0.,1.));
#811=DIRECTION('',(1.,0.,0.));
#812=AXIS2_PLACEMENT_3D('',#809,#810,#811);
#813=PLANE('',#812);
#814=ORIENTED_EDGE('',*,*,#470,.T.);
#815=DIRECTION('',(0.,1.,0.));
#816=VECTOR('',#815,1.);
#817=CARTESIAN_POINT('',(-0.381000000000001,-0.81,-5.69));
#818=LINE('',#817,#816);
#819=EDGE_CURVE('E814',#154,#461,#818,.T.);
#820=ORIENTED_EDGE('',*,*,#819,.F.);
#821=ORIENTED_EDGE('',*,*,#155,.F.);
#822=ORIENTED_EDGE('',*,*,#802,.T.);
#823=EDGE_LOOP('',(#814,#820,#821,#822));
#824=FACE_BOUND('',#823,.T.);
#825=ADVANCED_FACE('F569',(#824),#813,.F.);
#826=CARTESIAN_POINT('',(-0.381000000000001,-0.81,-5.69));
#827=DIRECTION('',(-0.996079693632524,0.,0.0884604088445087));
#828=DIRECTION('',(0.0884604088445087,0.,0.996079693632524));
#829=AXIS2_PLACEMENT_3D('',#826,#827,#828);
#830=PLANE('',#829);
#831=ORIENTED_EDGE('',*,*,#462,.T.);
#832=DIRECTION('',(0.,1.,0.));
#833=VECTOR('',#832,1.);
#834=CARTESIAN_POINT('',(-0.24901992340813,-0.81,-4.2038812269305));
#835=LINE('',#834,#833);
#836=EDGE_CURVE('E811',#162,#453,#835,.T.);
#837=ORIENTED_EDGE('',*,*,#836,.F.);
#838=ORIENTED_EDGE('',*,*,#163,.F.);
#839=ORIENTED_EDGE('',*,*,#819,.T.);
#840=EDGE_LOOP('',(#831,#837,#838,#839));
#841=FACE_BOUND('',#840,.T.);
#842=ADVANCED_FACE('F559',(#841),#830,.F.);
#843=CARTESIAN_POINT('',(0.,-0.81,-4.22599632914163));
#844=DIRECTION('',(0.,1.,0.));
#845=DIRECTION('',(0.,0.,1.));
#846=AXIS2_PLACEMENT_3D('',#843,#844,#845);
#847=CYLINDRICAL_SURFACE('',#846,0.25);
#848=ORIENTED_EDGE('',*,*,#454,.T.);
#849=DIRECTION('',(0.,1.,0.));
#850=VECTOR('',#849,1.);
#851=CARTESIAN_POINT('',(0.249019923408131,-0.81,-4.2038812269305));
#852=LINE('',#851,#850);
#853=EDGE_CURVE('E808',#171,#444,#852,.T.);
#854=ORIENTED_EDGE('',*,*,#853,.F.);
#855=ORIENTED_EDGE('',*,*,#172,.F.);
#856=ORIENTED_EDGE('',*,*,#836,.T.);
#857=EDGE_LOOP('',(#848,#854,#855,#856));
#858=FACE_BOUND('',#857,.T.);
#859=ADVANCED_FACE('F549',(#858),#847,.F.);
#860=CARTESIAN_POINT('',(0.381000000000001,-0.81,-5.69));
#861=DIRECTION('',(0.996079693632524,0.,0.0884604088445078));
#862=DIRECTION('',(0.0884604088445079,0.,-0.996079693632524));
#863=AXIS2_PLACEMENT_3D('',#860,#861,#862);
#864=PLANE('',#863);
#865=ORIENTED_EDGE('',*,*,#445,.T.);
#866=DIRECTION('',(0.,1.,0.));
#867=VECTOR('',#866,1.);
#868=CARTESIAN_POINT('',(0.381000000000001,-0.81,-5.69));
#869=LINE('',#868,#867);
#870=EDGE_CURVE('E805',#179,#436,#869,.T.);
#871=ORIENTED_EDGE('',*,*,#870,.F.);
#872=ORIENTED_EDGE('',*,*,#180,.F.);
#873=ORIENTED_EDGE('',*,*,#853,.T.);
#874=EDGE_LOOP('',(#865,#871,#872,#873));
#875=FACE_BOUND('',#874,.T.);
#876=ADVANCED_FACE('F539',(#875),#864,.F.);
#877=CARTESIAN_POINT('',(0.381000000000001,-0.81,-5.69));
#878=DIRECTION('',(0.,0.,1.));
#879=DIRECTION('',(1.,0.,0.));
#880=AXIS2_PLACEMENT_3D('',#877,#878,#879);
#881=PLANE('',#880);
#882=ORIENTED_EDGE('',*,*,#437,.T.);
#883=DIRECTION('',(0.,1.,0.));
#884=VECTOR('',#883,1.);
#885=CARTESIAN_POINT('',(1.143,-0.81,-5.69));
#886=LINE('',#885,#884);
#887=EDGE_CURVE('E802',#187,#428,#886,.T.);
#888=ORIENTED_EDGE('',*,*,#887,.F.);
#889=ORIENTED_EDGE('',*,*,#188,.F.);
#890=ORIENTED_EDGE('',*,*,#870,.T.);
#891=EDGE_LOOP('',(#882,#888,#889,#890));
#892=FACE_BOUND('',#891,.T.);
#893=ADVANCED_FACE('F529',(#892),#881,.F.);
#894=CARTESIAN_POINT('',(1.143,-0.81,-5.69));
#895=DIRECTION('',(-0.984807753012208,0.,0.173648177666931));
#896=DIRECTION('',(0.173648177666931,0.,0.984807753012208));
#897=AXIS2_PLACEMENT_3D('',#894,#895,#896);
#898=PLANE('',#897);
#899=ORIENTED_EDGE('',*,*,#429,.T.);
#900=DIRECTION('',(0.,1.,0.));
#901=VECTOR('',#900,1.);
#902=CARTESIAN_POINT('',(1.40879806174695,-0.81,-4.18258428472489));
#903=LINE('',#902,#901);
#904=EDGE_CURVE('E799',#195,#420,#903,.T.);
#905=ORIENTED_EDGE('',*,*,#904,.F.);
#906=ORIENTED_EDGE('',*,*,#196,.F.);
#907=ORIENTED_EDGE('',*,*,#887,.T.);
#908=EDGE_LOOP('',(#899,#905,#906,#907));
#909=FACE_BOUND('',#908,.T.);
#910=ADVANCED_FACE('F519',(#909),#898,.F.);
#911=CARTESIAN_POINT('',(1.655,-0.81,-4.22599632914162));
#912=DIRECTION('',(0.,1.,0.));
#913=DIRECTION('',(0.,0.,1.));
#914=AXIS2_PLACEMENT_3D('',#911,#912,#913);
#915=CYLINDRICAL_SURFACE('',#914,0.25);
#916=ORIENTED_EDGE('',*,*,#421,.T.);
#917=DIRECTION('',(0.,1.,0.));
#918=VECTOR('',#917,1.);
#919=CARTESIAN_POINT('',(1.905,-0.81,-4.22599632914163));
#920=LINE('',#919,#918);
#921=EDGE_CURVE('E796',#204,#411,#920,.T.);
#922=ORIENTED_EDGE('',*,*,#921,.F.);
#923=ORIENTED_EDGE('',*,*,#205,.F.);
#924=ORIENTED_EDGE('',*,*,#904,.T.);
#925=EDGE_LOOP('',(#916,#922,#923,#924));
#926=FACE_BOUND('',#925,.T.);
#927=ADVANCED_FACE('F509',(#926),#915,.F.);
#928=CARTESIAN_POINT('',(1.905,-0.81,-4.22599632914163));
#929=DIRECTION('',(1.,0.,0.));
#930=DIRECTION('',(0.,0.,-1.));
#931=AXIS2_PLACEMENT_3D('',#928,#929,#930);
#932=PLANE('',#931);
#933=ORIENTED_EDGE('',*,*,#412,.T.);
#934=DIRECTION('',(0.,1.,0.));
#935=VECTOR('',#934,1.);
#936=CARTESIAN_POINT('',(1.905,-0.81,-7.595));
#937=LINE('',#936,#935);
#938=EDGE_CURVE('E793',#212,#403,#937,.T.);
#939=ORIENTED_EDGE('',*,*,#938,.F.);
#940=ORIENTED_EDGE('',*,*,#213,.F.);
#941=ORIENTED_EDGE('',*,*,#921,.T.);
#942=EDGE_LOOP('',(#933,#939,#940,#941));
#943=FACE_BOUND('',#942,.T.);
#944=ADVANCED_FACE('F499',(#943),#932,.F.);
#945=CARTESIAN_POINT('',(1.905,-0.81,-7.595));
#946=DIRECTION('',(0.988993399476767,0.,0.147959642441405));
#947=DIRECTION('',(0.147959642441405,0.,-0.988993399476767));
#948=AXIS2_PLACEMENT_3D('',#945,#946,#947);
#949=PLANE('',#948);
#950=ORIENTED_EDGE('',*,*,#404,.T.);
#951=DIRECTION('',(0.,1.,0.));
#952=VECTOR('',#951,1.);
#953=CARTESIAN_POINT('',(2.15813234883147,-0.81,-9.28698991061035));
#954=LINE('',#953,#952);
#955=EDGE_CURVE('E790',#220,#395,#954,.T.);
#956=ORIENTED_EDGE('',*,*,#955,.F.);
#957=ORIENTED_EDGE('',*,*,#221,.F.);
#958=ORIENTED_EDGE('',*,*,#938,.T.);
#959=EDGE_LOOP('',(#950,#956,#957,#958));
#960=FACE_BOUND('',#959,.T.);
#961=ADVANCED_FACE('F489',(#960),#949,.F.);
#962=CARTESIAN_POINT('',(2.40538069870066,-0.81,-9.25));
#963=DIRECTION('',(0.,1.,0.));
#964=DIRECTION('',(0.,0.,1.));
#965=AXIS2_PLACEMENT_3D('',#962,#963,#964);
#966=CYLINDRICAL_SURFACE('',#965,0.25);
#967=ORIENTED_EDGE('',*,*,#396,.T.);
#968=DIRECTION('',(0.,1.,0.));
#969=VECTOR('',#968,1.);
#970=CARTESIAN_POINT('',(2.40538069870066,-0.81,-9.5));
#971=LINE('',#970,#969);
#972=EDGE_CURVE('E787',#229,#386,#971,.T.);
#973=ORIENTED_EDGE('',*,*,#972,.F.);
#974=ORIENTED_EDGE('',*,*,#230,.F.);
#975=ORIENTED_EDGE('',*,*,#955,.T.);
#976=EDGE_LOOP('',(#967,#973,#974,#975));
#977=FACE_BOUND('',#976,.T.);
#978=ADVANCED_FACE('F479',(#977),#966,.T.);
#979=CARTESIAN_POINT('',(2.67461930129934,-0.81,-9.5));
#980=DIRECTION('',(0.,0.,1.));
#981=DIRECTION('',(1.,0.,0.));
#982=AXIS2_PLACEMENT_3D('',#979,#980,#981);
#983=PLANE('',#982);
#984=ORIENTED_EDGE('',*,*,#387,.T.);
#985=DIRECTION('',(0.,1.,0.));
#986=VECTOR('',#985,1.);
#987=CARTESIAN_POINT('',(2.67461930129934,-0.81,-9.5));
#988=LINE('',#987,#986);
#989=EDGE_CURVE('E784',#237,#378,#988,.T.);
#990=ORIENTED_EDGE('',*,*,#989,.F.);
#991=ORIENTED_EDGE('',*,*,#238,.F.);
#992=ORIENTED_EDGE('',*,*,#972,.T.);
#993=EDGE_LOOP('',(#984,#990,#991,#992));
#994=FACE_BOUND('',#993,.T.);
#995=ADVANCED_FACE('F469',(#994),#983,.F.);
#996=CARTESIAN_POINT('',(2.67461930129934,-0.81,-9.25));
#997=DIRECTION('',(0.,1.,0.));
#998=DIRECTION('',(0.,0.,1.));
#999=AXIS2_PLACEMENT_3D('',#996,#997,#998);
#1000=CYLINDRICAL_SURFACE('',#999,0.25);
#1001=ORIENTED_EDGE('',*,*,#379,.T.);
#1002=DIRECTION('',(0.,1.,0.));
#1003=VECTOR('',#1002,1.);
#1004=CARTESIAN_POINT('',(2.92186765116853,-0.81,-9.28698991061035));
#1005=LINE('',#1004,#1003);
#1006=EDGE_CURVE('E781',#246,#369,#1005,.T.);
#1007=ORIENTED_EDGE('',*,*,#1006,.F.);
#1008=ORIENTED_EDGE('',*,*,#247,.F.);
#1009=ORIENTED_EDGE('',*,*,#989,.T.);
#1010=EDGE_LOOP('',(#1001,#1007,#1008,#1009));
#1011=FACE_BOUND('',#1010,.T.);
#1012=ADVANCED_FACE('F459',(#1011),#1000,.T.);
#1013=CARTESIAN_POINT('',(3.175,-0.81,-7.595));
#1014=DIRECTION('',(-0.988993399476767,0.,0.147959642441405));
#1015=DIRECTION('',(0.147959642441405,0.,0.988993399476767));
#1016=AXIS2_PLACEMENT_3D('',#1013,#1014,#1015);
#1017=PLANE('',#1016);
#1018=ORIENTED_EDGE('',*,*,#370,.T.);
#1019=DIRECTION('',(0.,1.,0.));
#1020=VECTOR('',#1019,1.);
#1021=CARTESIAN_POINT('',(3.175,-0.81,-7.595));
#1022=LINE('',#1021,#1020);
#1023=EDGE_CURVE('E778',#254,#361,#1022,.T.);
#1024=ORIENTED_EDGE('',*,*,#1023,.F.);
#1025=ORIENTED_EDGE('',*,*,#255,.F.);
#1026=ORIENTED_EDGE('',*,*,#1006,.T.);
#1027=EDGE_LOOP('',(#1018,#1024,#1025,#1026));
#1028=FACE_BOUND('',#1027,.T.);
#1029=ADVANCED_FACE('F449',(#1028),#1017,.F.);
#1030=CARTESIAN_POINT('',(3.175,-0.81,-5.69));
#1031=DIRECTION('',(-1.,0.,0.));
#1032=DIRECTION('',(0.,0.,1.));
#1033=AXIS2_PLACEMENT_3D('',#1030,#1031,#1032);
#1034=PLANE('',#1033);
#1035=ORIENTED_EDGE('',*,*,#362,.T.);
#1036=DIRECTION('',(0.,1.,0.));
#1037=VECTOR('',#1036,1.);
#1038=CARTESIAN_POINT('',(3.175,-0.81,-5.69));
#1039=LINE('',#1038,#1037);
#1040=EDGE_CURVE('E775',#262,#353,#1039,.T.);
#1041=ORIENTED_EDGE('',*,*,#1040,.F.);
#1042=ORIENTED_EDGE('',*,*,#263,.F.);
#1043=ORIENTED_EDGE('',*,*,#1023,.T.);
#1044=EDGE_LOOP('',(#1035,#1041,#1042,#1043));
#1045=FACE_BOUND('',#1044,.T.);
#1046=ADVANCED_FACE('F439',(#1045),#1034,.F.);
#1047=CARTESIAN_POINT('',(3.96,-0.81,-5.69));
#1048=DIRECTION('',(0.,0.,1.));
#1049=DIRECTION('',(1.,0.,0.));
#1050=AXIS2_PLACEMENT_3D('',#1047,#1048,#1049);
#1051=PLANE('',#1050);
#1052=ORIENTED_EDGE('',*,*,#354,.T.);
#1053=DIRECTION('',(0.,1.,0.));
#1054=VECTOR('',#1053,1.);
#1055=CARTESIAN_POINT('',(3.96,-0.81,-5.69));
#1056=LINE('',#1055,#1054);
#1057=EDGE_CURVE('E772',#270,#345,#1056,.T.);
#1058=ORIENTED_EDGE('',*,*,#1057,.F.);
#1059=ORIENTED_EDGE('',*,*,#271,.F.);
#1060=ORIENTED_EDGE('',*,*,#1040,.T.);
#1061=EDGE_LOOP('',(#1052,#1058,#1059,#1060));
#1062=FACE_BOUND('',#1061,.T.);
#1063=ADVANCED_FACE('F429',(#1062),#1051,.F.);
#1064=CARTESIAN_POINT('',(3.96,-0.81,-3.4));
#1065=DIRECTION('',(-1.,0.,0.));
#1066=DIRECTION('',(0.,0.,1.));
#1067=AXIS2_PLACEMENT_3D('',#1064,#1065,#1066);
#1068=PLANE('',#1067);
#1069=ORIENTED_EDGE('',*,*,#346,.T.);
#1070=DIRECTION('',(0.,1.,0.));
#1071=VECTOR('',#1070,1.);
#1072=CARTESIAN_POINT('',(3.96,-0.81,-3.4));
#1073=LINE('',#1072,#1071);
#1074=EDGE_CURVE('E768',#278,#337,#1073,.T.);
#1075=ORIENTED_EDGE('',*,*,#1074,.F.);
#1076=ORIENTED_EDGE('',*,*,#279,.F.);
#1077=ORIENTED_EDGE('',*,*,#1057,.T.);
#1078=EDGE_LOOP('',(#1069,#1075,#1076,#1077));
#1079=FACE_BOUND('',#1078,.T.);
#1080=ADVANCED_FACE('F419',(#1079),#1068,.F.);
#1081=CARTESIAN_POINT('',(3.175,-0.81,-3.4));
#1082=DIRECTION('',(0.,0.,-1.));
#1083=DIRECTION('',(-1.,0.,0.));
#1084=AXIS2_PLACEMENT_3D('',#1081,#1082,#1083);
#1085=PLANE('',#1084);
#1086=ORIENTED_EDGE('',*,*,#338,.T.);
#1087=DIRECTION('',(0.,1.,0.));
#1088=VECTOR('',#1087,1.);
#1089=CARTESIAN_POINT('',(3.175,-0.81,-3.4));
#1090=LINE('',#1089,#1088);
#1091=EDGE_CURVE('E765',#29,#329,#1090,.T.);
#1092=ORIENTED_EDGE('',*,*,#1091,.F.);
#1093=ORIENTED_EDGE('',*,*,#285,.F.);
#1094=ORIENTED_EDGE('',*,*,#1074,.T.);
#1095=EDGE_LOOP('',(#1086,#1092,#1093,#1094));
#1096=FACE_BOUND('',#1095,.T.);
#1097=ADVANCED_FACE('F336',(#1096),#1085,.F.);
#1098=CARTESIAN_POINT('',(3.175,-0.81,4.52));
#1099=DIRECTION('',(-1.,0.,0.));
#1100=DIRECTION('',(0.,0.,1.));
#1101=AXIS2_PLACEMENT_3D('',#1098,#1099,#1100);
#1102=PLANE('',#1101);
#1103=ORIENTED_EDGE('',*,*,#330,.T.);
#1104=DIRECTION('',(0.,-1.,0.));
#1105=VECTOR('',#1104,1.);
#1106=CARTESIAN_POINT('',(3.175,-0.81,3.52));
#1107=LINE('',#1106,#1105);
#1108=EDGE_CURVE('E11',#321,#31,#1107,.T.);
#1109=ORIENTED_EDGE('',*,*,#1108,.T.);
#1110=ORIENTED_EDGE('',*,*,#32,.F.);
#1111=ORIENTED_EDGE('',*,*,#1091,.T.);
#1112=EDGE_LOOP('',(#1103,#1109,#1110,#1111));
#1113=FACE_BOUND('',#1112,.T.);
#1114=ADVANCED_FACE('F328',(#1113),#1102,.F.);
#1115=CARTESIAN_POINT('',(-3.175,-0.81,4.52));
#1116=DIRECTION('',(0.,0.,-1.));
#1117=DIRECTION('',(-1.,0.,0.));
#1118=AXIS2_PLACEMENT_3D('',#1115,#1116,#1117);
#1119=PLANE('',#1118);
#1120=DIRECTION('',(-1.,0.,0.));
#1121=VECTOR('',#1120,1.);
#1122=CARTESIAN_POINT('',(-3.175,-0.176326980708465,4.52));
#1123=LINE('',#1122,#1121);
#1124=CARTESIAN_POINT('',(2.175,-0.176326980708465,4.52));
#1125=VERTEX_POINT('',#1124);
#1126=CARTESIAN_POINT('',(-2.175,-0.176326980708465,4.52));
#1127=VERTEX_POINT('',#1126);
#1128=EDGE_CURVE('E290',#1125,#1127,#1123,.T.);
#1129=ORIENTED_EDGE('',*,*,#1128,.T.);
#1130=DIRECTION('',(0.,-1.,0.));
#1131=VECTOR('',#1130,1.);
#1132=CARTESIAN_POINT('',(-2.175,-0.81,4.52));
#1133=LINE('',#1132,#1131);
#1134=CARTESIAN_POINT('',(-2.17499999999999,-0.633673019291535,4.52));
#1135=VERTEX_POINT('',#1134);
#1136=EDGE_CURVE('E56',#1127,#1135,#1133,.T.);
#1137=ORIENTED_EDGE('',*,*,#1136,.T.);
#1138=DIRECTION('',(1.,0.,0.));
#1139=VECTOR('',#1138,1.);
#1140=CARTESIAN_POINT('',(3.175,-0.633673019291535,4.52));
#1141=LINE('',#1140,#1139);
#1142=CARTESIAN_POINT('',(2.175,-0.633673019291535,4.52));
#1143=VERTEX_POINT('',#1142);
#1144=EDGE_CURVE('E283',#1135,#1143,#1141,.T.);
#1145=ORIENTED_EDGE('',*,*,#1144,.T.);
#1146=DIRECTION('',(0.,1.,0.));
#1147=VECTOR('',#1146,1.);
#1148=CARTESIAN_POINT('',(2.175,-0.81,4.52));
#1149=LINE('',#1148,#1147);
#1150=EDGE_CURVE('E301',#1143,#1125,#1149,.T.);
#1151=ORIENTED_EDGE('',*,*,#1150,.T.);
#1152=EDGE_LOOP('',(#1129,#1137,#1145,#1151));
#1153=FACE_BOUND('',#1152,.T.);
#1154=ADVANCED_FACE('F325',(#1153),#1119,.F.);
#1155=CARTESIAN_POINT('',(0.,-0.81,0.));
#1156=DIRECTION('',(0.,1.,0.));
#1157=DIRECTION('',(0.,0.,1.));
#1158=AXIS2_PLACEMENT_3D('',#1155,#1156,#1157);
#1159=CYLINDRICAL_SURFACE('',#1158,0.75);
#1160=ORIENTED_EDGE('',*,*,#296,.T.);
#1161=EDGE_LOOP('',(#1160));
#1162=FACE_BOUND('',#1161,.T.);
#1163=ORIENTED_EDGE('',*,*,#578,.F.);
#1164=EDGE_LOOP('',(#1163));
#1165=FACE_BOUND('',#1164,.T.);
#1166=ADVANCED_FACE('F327',(#1162,#1165),#1159,.F.);
#1167=CARTESIAN_POINT('',(-2.67461930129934,-0.81,3.51999999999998));
#1168=DIRECTION('',(0.,-0.984807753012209,0.173648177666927));
#1169=DIRECTION('',(0.,-0.173648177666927,-0.984807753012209));
#1170=AXIS2_PLACEMENT_3D('',#1167,#1168,#1169);
#1171=PLANE('',#1170);
#1172=ORIENTED_EDGE('',*,*,#1144,.F.);
#1173=DIRECTION('',(0.701673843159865,0.123724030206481,0.701673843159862));
#1174=VECTOR('',#1173,1.);
#1175=CARTESIAN_POINT('',(-2.92863947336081,-0.766559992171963,3.76636052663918));
#1176=LINE('',#1175,#1174);
#1177=EDGE_CURVE('E42',#1135,#39,#1176,.F.);
#1178=ORIENTED_EDGE('',*,*,#1177,.T.);
#1179=ORIENTED_EDGE('',*,*,#40,.F.);
#1180=DIRECTION('',(0.701673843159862,-0.123724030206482,-0.701673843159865));
#1181=VECTOR('',#1180,1.);
#1182=CARTESIAN_POINT('',(0.294962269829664,-0.302171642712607,6.40003773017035));
#1183=LINE('',#1182,#1181);
#1184=EDGE_CURVE('E49',#31,#1143,#1183,.F.);
#1185=ORIENTED_EDGE('',*,*,#1184,.T.);
#1186=EDGE_LOOP('',(#1172,#1178,#1179,#1185));
#1187=FACE_BOUND('',#1186,.T.);
#1188=ADVANCED_FACE('F306',(#1187),#1171,.T.);
#1189=CARTESIAN_POINT('',(-3.175,-0.176326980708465,4.52));
#1190=DIRECTION('',(0.,-0.984807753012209,-0.173648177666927));
#1191=DIRECTION('',(0.,0.173648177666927,-0.984807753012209));
#1192=AXIS2_PLACEMENT_3D('',#1189,#1190,#1191);
#1193=PLANE('',#1192);
#1194=ORIENTED_EDGE('',*,*,#322,.F.);
#1195=DIRECTION('',(0.701673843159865,-0.123724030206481,0.701673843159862));
#1196=VECTOR('',#1195,1.);
#1197=CARTESIAN_POINT('',(-2.66734618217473,-0.0895130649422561,4.02765381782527));
#1198=LINE('',#1197,#1196);
#1199=EDGE_CURVE('E299',#311,#1127,#1198,.T.);
#1200=ORIENTED_EDGE('',*,*,#1199,.T.);
#1201=ORIENTED_EDGE('',*,*,#1128,.F.);
#1202=DIRECTION('',(0.701673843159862,0.123724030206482,-0.701673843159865));
#1203=VECTOR('',#1202,1.);
#1204=CARTESIAN_POINT('',(-0.459052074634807,-0.640781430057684,7.15405207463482));
#1205=LINE('',#1204,#1203);
#1206=EDGE_CURVE('E297',#1125,#321,#1205,.T.);
#1207=ORIENTED_EDGE('',*,*,#1206,.T.);
#1208=EDGE_LOOP('',(#1194,#1200,#1201,#1207));
#1209=FACE_BOUND('',#1208,.T.);
#1210=ADVANCED_FACE('F320',(#1209),#1193,.F.);
#1211=CARTESIAN_POINT('',(-3.175,-0.81,3.52));
#1212=DIRECTION('',(0.707106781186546,0.,-0.707106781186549));
#1213=DIRECTION('',(-0.707106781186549,0.,-0.707106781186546));
#1214=AXIS2_PLACEMENT_3D('',#1211,#1212,#1213);
#1215=PLANE('',#1214);
#1216=ORIENTED_EDGE('',*,*,#1177,.F.);
#1217=ORIENTED_EDGE('',*,*,#1136,.F.);
#1218=ORIENTED_EDGE('',*,*,#1199,.F.);
#1219=ORIENTED_EDGE('',*,*,#593,.F.);
#1220=EDGE_LOOP('',(#1216,#1217,#1218,#1219));
#1221=FACE_BOUND('',#1220,.T.);
#1222=ADVANCED_FACE('F308',(#1221),#1215,.F.);
#1223=CARTESIAN_POINT('',(2.175,-0.81,4.52));
#1224=DIRECTION('',(-0.707106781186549,0.,-0.707106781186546));
#1225=DIRECTION('',(-0.707106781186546,0.,0.707106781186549));
#1226=AXIS2_PLACEMENT_3D('',#1223,#1224,#1225);
#1227=PLANE('',#1226);
#1228=ORIENTED_EDGE('',*,*,#1184,.F.);
#1229=ORIENTED_EDGE('',*,*,#1108,.F.);
#1230=ORIENTED_EDGE('',*,*,#1206,.F.);
#1231=ORIENTED_EDGE('',*,*,#1150,.F.);
#1232=EDGE_LOOP('',(#1228,#1229,#1230,#1231));
#1233=FACE_BOUND('',#1232,.T.);
#1234=ADVANCED_FACE('F36',(#1233),#1227,.F.);
#1235=CLOSED_SHELL('',(#300,#582,#604,#621,#638,#655,#672,#689,#706,#723,#740,#757,#774,#791,
#808,#825,#842,#859,#876,#893,#910,#927,#944,#961,#978,#995,#1012,#1029,#1046,#1063,#1080,#1097,
#1114,#1154,#1166,#1188,#1210,#1222,#1234));
#1236=MANIFOLD_SOLID_BREP('B2',#1235);
#1237=ADVANCED_BREP_SHAPE_REPRESENTATION('',(#18,#1236),#14);
#1238=SHAPE_DEFINITION_REPRESENTATION(#9,#1237);
ENDSEC;
END-ISO-10303-21;
